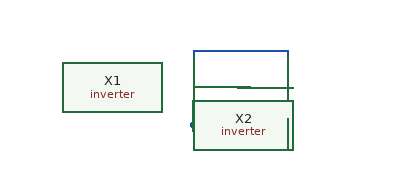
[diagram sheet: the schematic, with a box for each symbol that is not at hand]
v {xschem version=2.9.9 file_version=1.2 }
G {}
K {}
V {}
S {}
E {}
N 115 -35 125 -35 {}
N 155 -65 155 -60 {}
N 80 -65 155 -65 {}
N 80 -65 80 -60 {}
N 80 -10 80 -5 {}
N 80 -5 155 -5 {}
N 155 -10 155 -5 {}
N 80 -5 80 -0 {}
C {/home/madvlsi/Documents/inverter_tutorial/inverter.sym} 15 -35 0 0 {name=X1}
C {/home/madvlsi/Documents/inverter_tutorial/inverter.sym} 90 -35 0 0 {name=X2}
